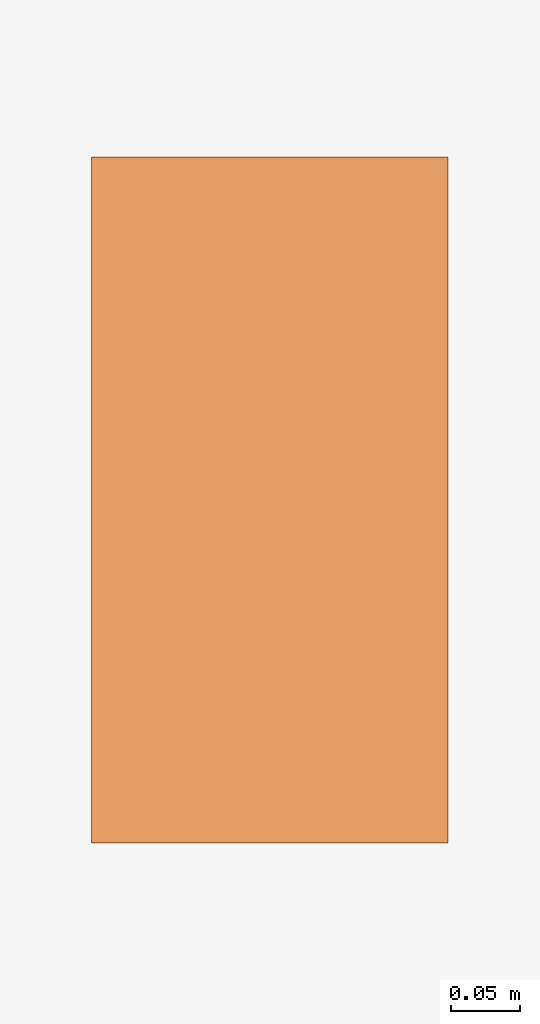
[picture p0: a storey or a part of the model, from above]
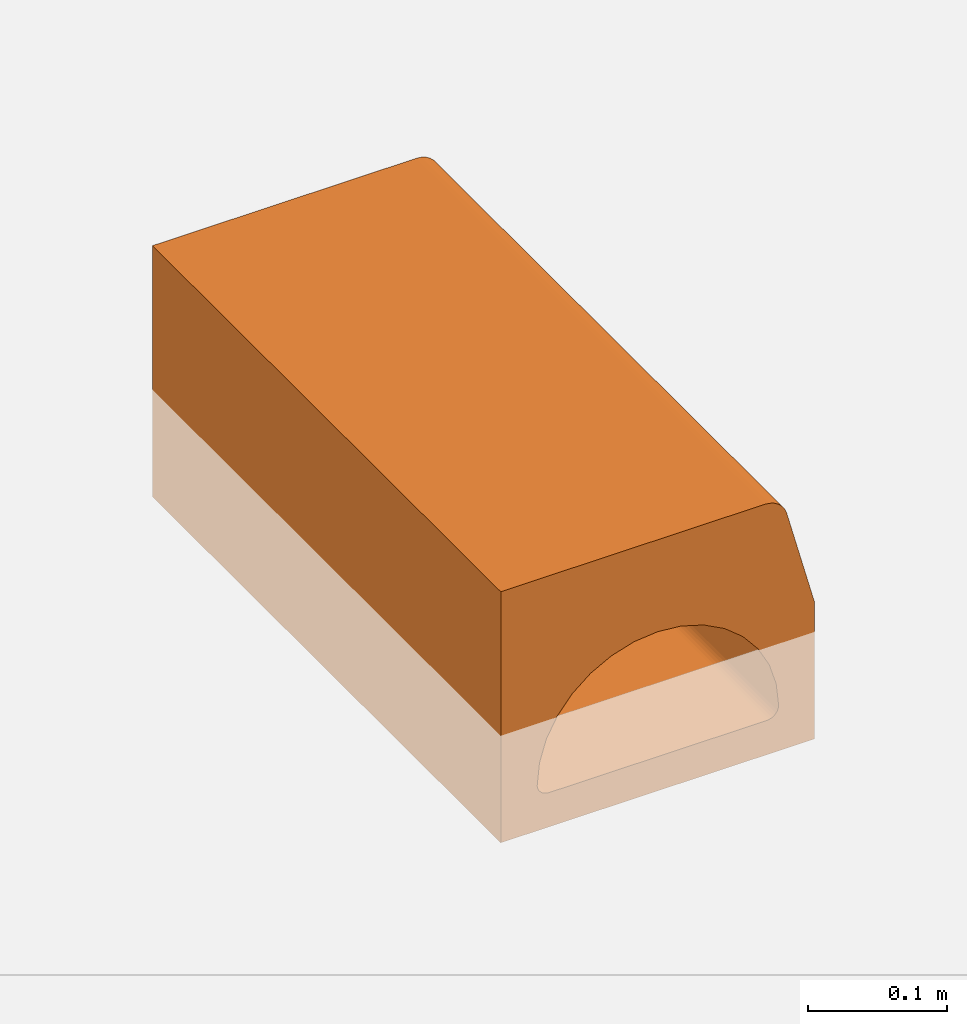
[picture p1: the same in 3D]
Properties of the parts of a building model (IFC2X3)

# File
Description: ViewDefinition [CoordinationView]
File name: T0128 - Blind Channel - 500mm LG - 220mm High.ifc
Time: 2013-09-04T09:01:34
Written by: Autodesk Revit 2013
Made in: 20120221_2030(x64)

# IfcProject, Project Number
LongName: Project Name; Phase: Project Status

# IfcSite, Default
RefLatitude: 42, 21, 30, 344238; RefLongitude: -71, -3, -35, -194702; RefElevation: 0 mm

# IfcBuilding
Pset_BuildingCommon - NumberOfStoreys: 1
Other - Project Name: Project Name; Project Status: Project Status; Client Name: Owner; Project Issue Date: Issue Date; Project Number: Project Number; Project Address: ## Street City, State Zip

# IfcBuildingStorey, Level 1
LongName: Level 1; Elevation: 0 mm
Constraints - Elevation Base: 0; Elevation: 0 mm
Graphics - Symbol at End 1 Default: no; Color: 0; Line Pattern: Center; Symbol: M_Level Head - Circle: M_Level Head - Circle; Symbol at End 2 Default: yes; Line Weight: 1
Identity Data - Structural: no; Name: Level 1; Building Story: yes
Dimensions - Computation Height: 0 mm

# IfcBuildingElementProxy: T0128 - Blind Channel - 500mm LG - 220mm High, Civil-Drainage-Channel-ACO-KerbDrain-KD200:T0128 - Blind Channel - 500mm LG - 220mm High:T0128 - Blind Channel - 500mm LG - 220mm High:308203
In: Level 1
Material: ACO Polymer Concrete.
Constraints - Level: Level: Level 1; Moves With Nearby Elements: no
Dimensions - Volume: 19124281 mm3; Void Depth.: -95 mm; Void length: 500 mm
Phasing - Phase Created: New Construction
Pset_BuildingElementProxyCommon - Reference: T0128 - Blind Channel - 500mm LG - 220mm High
Materials and Finishes - Access Cover/Frame Colour: N/A; Access Cover/Frame Material: N/A; Access Cover/Frame Finish: N/A; End Cap Material: N/A; End Cap Colour: N/A; Channel Colour: Grey; Channel Material: Vienite® Synthetic Resin Concrete
Identity Data - Product Code: T0128; OmniClass Title: Rainwater Removal; Model: ACO KerbDrain KD200; Installation guidelines: http://www.aco.co.uk/download.php?id=120; Assembly Code: D2040; Product Page URL: http://www.aco.co.uk/product_detail.php?id=3; Address: ACO Business Park, Hitchin Road, Shefford, Bedfordshire, United Kingdom SG17 5TE; OmniClass Number: 23.70.50.24; Product brochure: http://www.aco.co.uk/download.php?id=120; Cost: 0; Manufacturer: ACO Technologies plc - ACO Water Management Division; Type Comments: ACO KerbDrain KD200 half battered blind kerb unit 220 high 500mm long; Price: POA - contact ACO; Maintenance guidelines: http://www.aco.co.uk/download.php?id=120; Model Description: Combined kerb and drainage system; e-mail Sales: customersupport@aco.co.uk; Telephone: +44 (0)1462 816666; Assembly Description: Rain Water Drainage; URL: www.aco.co.uk; e-mail Technical: technical@aco.co.uk; Fax: +44 (0)1462 815895
General - SerialNumber: 0.000000; TagNumber: 0.000000
Data - Hydraulic Performance: http://www.aco.co.uk/download.php?id=120; Product Standard: BS EN 1433:2002, CE marked, Kitemarked; Drainage Slot Intake area: N/A; Product Weight: 40.6 Kg; Installation - Concrete Grade: Refer to brochure; Invert Depth: 190mm; Product Dimensions: 500mm x 260mm x 220mm (LxWxH); Load Class: A 15 - D 400 A 15 - D 400; Drainage Slot Width: N/A; Channel C.S.A: 0.02m²; Concrete Surround Volume - Load Class A 15 - D 400 - Concrete Pavement: 0.20m³/m; ACO Hydraulic Design Software: http://www.acodesign.co.uk
Green Building Properties - End Cap Recycled Material Content: N/A; Access Cover/Frame Recycled Material Content: N/A; End Cap Recyclable: N/A; Channel Recyclable: Fully recyclable; Access Cover/Frame Recyclable: N/A; Channel Recycled Material Content: 20% minimum
Construction - Blindunit_220: yes; Access Cover: no; Accessunit_235: no; Accessunit_220: no; Channelunit_220: no; Blindunit_235: no; Closing end cap: no; Channelunit_235: no
Other - Revision: 1; CreatedBy: www.aco.co.uk

# IfcOpeningElement: Recess
In: Level 1
Constraints - Related to Mass: no; Height Offset From Level: 0 mm; Room Bounding: yes; Level: Level: Level 1
Dimensions - Perimeter: 51360 mm; Volume: 60575650000 mm3; Thickness: 400 mm; Area: 151470000 mm2
Structural - Structural: no; Enable Analytical Model: no
Phasing - Phase Created: New Construction
Construction - Function: 0; Default Thickness: 400 mm
Analytical Properties - Absorptance: 0.1; Roughness: 1
Graphics - Coarse Scale Fill Color: 0
Materials and Finishes - Structural Material: Plant

# IfcSlab: Floor:Generic Floor - 400mm, Floor:Generic Floor - 400mm:193825
In: Level 1
PredefinedType: FLOOR; Material: Plant 400 mm
Constraints - Related to Mass: no; Height Offset From Level: 0 mm; Room Bounding: yes; Level: Level: Level 1
Dimensions - Perimeter: 51360 mm; Volume: 60575650000 mm3; Thickness: 400 mm; Area: 151470000 mm2
Structural - Structural: no; Enable Analytical Model: no
Phasing - Phase Created: New Construction
Pset_SlabCommon - Reference: Generic Floor - 400mm; IsExternal: no; LoadBearing: yes
Construction - Function: 0; Default Thickness: 400 mm
Analytical Properties - Absorptance: 0.1; Roughness: 1
Graphics - Coarse Scale Fill Color: 0
Materials and Finishes - Structural Material: Plant
